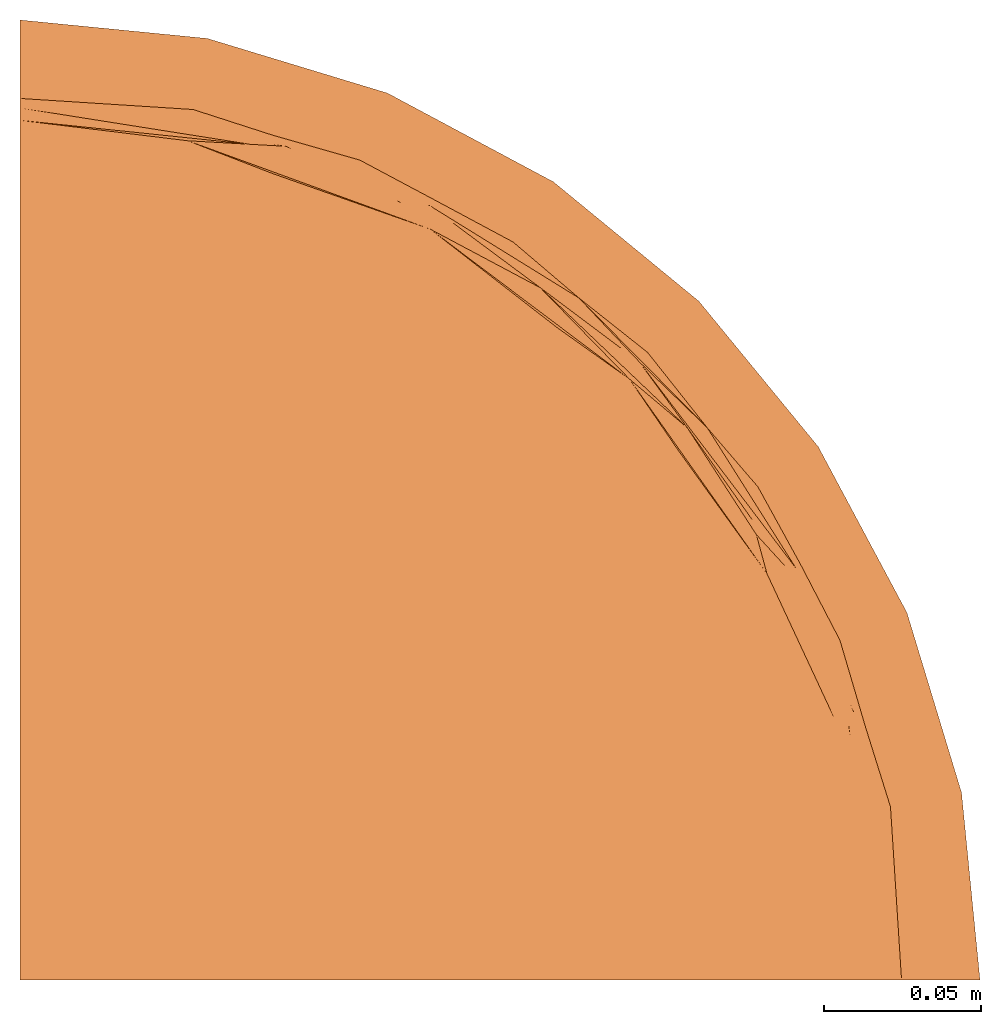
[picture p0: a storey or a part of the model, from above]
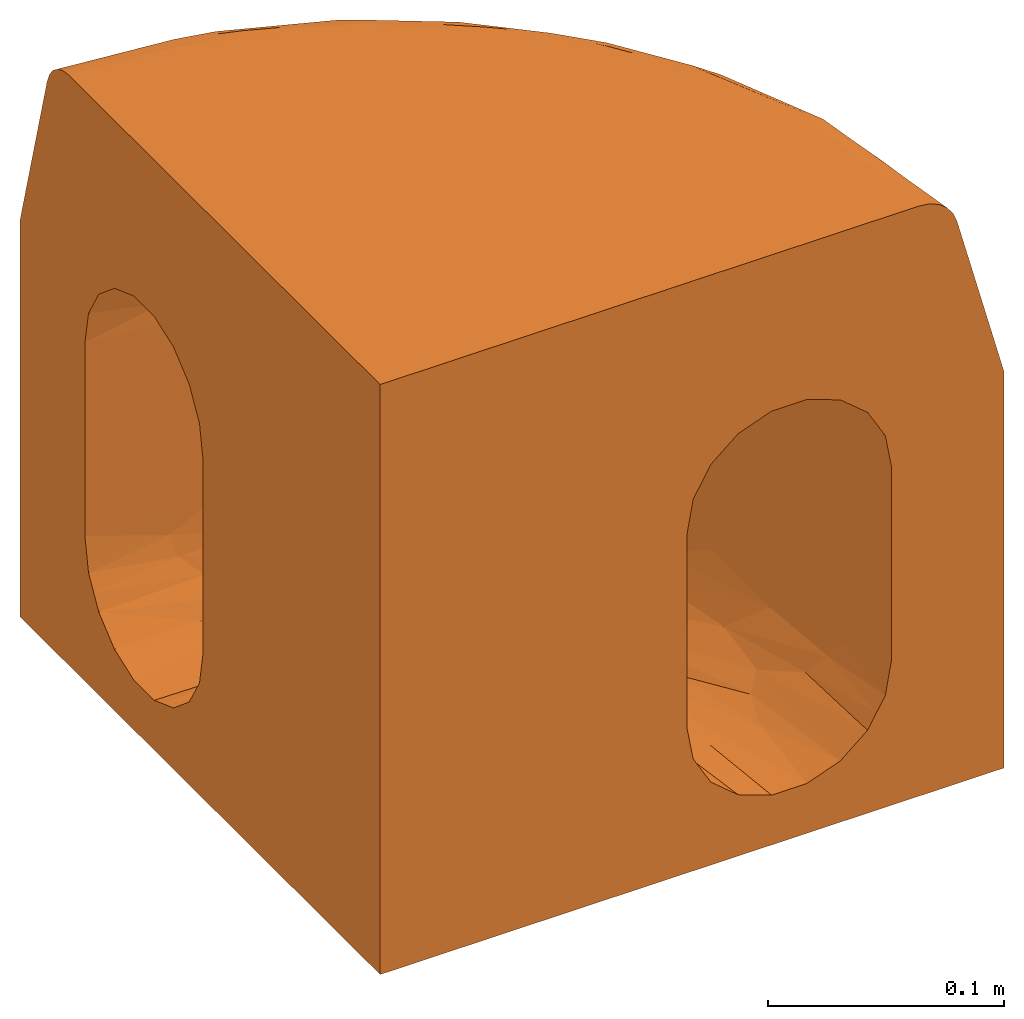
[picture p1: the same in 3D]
Properties of the parts of a building model (IFC2X3)

# File
Description: ViewDefinition [CoordinationView]
File name: 4992 - Quadrant.ifc
Time: 2013-09-12T12:54:35
Written by: Autodesk Revit 2013
Made in: 20120221_2030(x64)

# IfcProject, Project Number
LongName: Project Name; Phase: Project Status

# IfcSite, Default
RefLatitude: 42, 21, 30, 344238; RefLongitude: -71, -3, -35, -194702; RefElevation: 0 mm

# IfcBuilding
Pset_BuildingCommon - NumberOfStoreys: 2
Other - Project Issue Date: Issue Date; Project Number: Project Number; Project Status: Project Status; Client Name: Owner; Project Address: Enter address here; Project Name: Project Name

# IfcBuildingStorey (2)
Graphics - Symbol at End 2 Default: yes; Line Pattern: Center; Color: 0; Line Weight: 1; Symbol: M_Level Head - Circle: M_Level Head - Circle; Symbol at End 1 Default: no
Constraints - Elevation Base: 0
Identity Data - Structural: no; Building Story: yes
Dimensions - Computation Height: 0 mm
Name | LongName = Name | Elevation (mm) = Constraints, Elevation (mm)
T.O. Fnd. Wall | T.O. Fnd. Wall | -300
Level 1 | Level 1 | 0

# IfcBuildingElementProxy: 4992 - Quadrant, Civil-Drainage-Channel-ACO-KerbDrain-HB305 Part 2:4992 - Quadrant:4992 - Quadrant:263456
In: T.O. Fnd. Wall
Material: ACO Polymer Concrete.
Other - CreatedBy: www.aco.co.uk; Revision: 1
Green Building Properties - Access Cover/Frame Recyclable: N/A; Channel Recyclable: Fully recyclable; End Cap Recyclable: N/A; Channel Recycled Material Content: 20% minimum; Access Cover/Frame Recycled Material Content: N/A; End Cap Recycled Material Content: N/A
Identity Data - Price: POA - contact ACO; Cost: 0; e-mail Technical: technical@aco.co.uk; Address: ACO Business Park, Hitchin Road, Shefford, Bedfordshire, United Kingdom SG17 5TE; Product Page URL: http://www.aco.co.uk/product_detail.php?id=3; Product brochure: http://www.aco.co.uk/download.php?id=120; Model Description: Combined kerb and drainage system; Assembly Code: D2040; Type Comments: ACO KerbDrain HB305 half battered quadrant 305mm Long; OmniClass Title: Rainwater Removal; Installation guidelines: http://www.aco.co.uk/download.php?id=120; URL: www.aco.co.uk; Assembly Description: Rain Water Drainage; e-mail Sales: customersupport@aco.co.uk; Telephone: +44 (0)1462 816666; Maintenance guidelines: http://www.aco.co.uk/download.php?id=120; Product Code: 4992; Manufacturer: ACO Technologies plc - ACO Water Management Division; OmniClass Number: 23.70.50.24; Fax: +44 (0)1462 815895; Model: ACO KerbDrain HB305
Phasing - Phase Created: Phase 1
Constraints - Moves With Nearby Elements: no; Level: Level: Level 1
Dimensions - Volume: 16034384 mm3; Mitre Void Start: -7300 mm; Flush Drainable Centre Stone Void End: -4505 mm; Void_Width: 150 mm; 1.8m Radius Unit void End: -4805 mm; Curved LH Void End: 3010 mm; 6m Radius unit void Start: -6000 mm; Quadrant void Start: 0 mm; Quadrant void End: 180 mm; Curved RH Void Start: -2980 mm; Void L Start: -3000 mm; Curved RH Void End: -3000 mm; Straight Void Depth: 0 mm; Mitre Void End: -7305 mm; Flush Drainable Centre Stone Void Start: -4500 mm; Curved LH Void Start: 3000 mm; Void_Length: 25 mm; mitre small length: 487 mm; Void L End: -3010 mm; 1.8m Radius unit Void Start: -4800 mm; Staright Void Depth: -180 mm; 6m Radius Unit Void end: -6005 mm; Mite Long Side Length: 500 mm
Pset_BuildingElementProxyCommon - Reference: 4992 - Quadrant
General - SerialNumber: 0.000000; TagNumber: 0.000000
Data - Product Dimensions: 305mm x 305mm x 305mm (LxWxH); Channel C.S.A: 0.02m²; Product Weight: 32.0 Kg; Drainage Slot Intake area: N/A; Product Standard: BS EN 1433:2002, CE marked, Kitemarked; Load Class: A 15 - D 400; Installation - Concrete Grade: Refer to brochure; Invert Depth: 280mm; Drainage Slot Width: N/A; Hydraulic Performance: http://www.aco.co.uk/download.php?id=120; ACO Hydraulic Design Software: http://www.acodesign.co.uk; Concrete Surround Volume - Load Class A 15 - D 400 - Concrete Pavement: N/A; Connection Pipe O.D: N/A; Concrete Surround Volume - Load Class A 15 - D 400 - Grass or Asphalt Pavement: N/A
Construction - KDHB305 25-11m internal_mitre: no; LH drop kerb- 6m ext rad: no; KDHB305 25-11m external_mitre: no; KDHB305 6m _external_radius: no; flush drainable centre stone: no; KDHB305_quadrant: yes; KDHB305 7-6m external_mitre: no; KDHB305 1.8m_radius: no; KDHB305 internal_angle: no; KDHB305 RH drop kerb-4999: no; KDHB305 10-8m_external_mitre: no
Materials and Finishes - End Cap Colour: N/A; Access Cover/Frame Colour: N/A; Access Cover/Frame Material: N/A; Channel Colour: Grey; End Cap Material: N/A; Connection Pipe Material: N/A; Channel Material: Vienite® Synthetic Resin Concrete; Access Cover/Frame Finish: N/A; Connection Pipe Material Colour: N/A

# IfcOpeningElement: Recess (6)
In: Level 1
Constraints - Related to Mass: no; Level: Level: Level 1; Room Bounding: yes; Height Offset From Level: 0 mm
Dimensions - Volume: 11130419078 mm3; Area: 27858925 mm2; Perimeter: 21157.2 mm; Thickness: 400 mm
Phasing - Phase Created: Phase 1
Structural - Structural: no; Enable Analytical Model: no
Construction - Default Thickness: 400 mm; Function: 0
Graphics - Coarse Scale Fill Color: 0
Analytical Properties - Absorptance: 0.1; Roughness: 1

# IfcSlab: Floor:Generic Floor - 400mm, Floor:Generic Floor - 400mm:184025
In: Level 1
PredefinedType: FLOOR; Material: Default Floor 400 mm
Constraints - Related to Mass: no; Level: Level: Level 1; Room Bounding: yes; Height Offset From Level: 0 mm
Dimensions - Volume: 11130419078 mm3; Area: 27858925 mm2; Perimeter: 21157.2 mm; Thickness: 400 mm
Phasing - Phase Created: Phase 1
Structural - Structural: no; Enable Analytical Model: no
Pset_SlabCommon - Reference: Generic Floor - 400mm; IsExternal: no; LoadBearing: yes
Construction - Default Thickness: 400 mm; Function: 0
Graphics - Coarse Scale Fill Color: 0
Analytical Properties - Absorptance: 0.1; Roughness: 1
